VERSION 5.7 ;
  NOWIREEXTENSIONATPIN ON ;
  DIVIDERCHAR "/" ;
  BUSBITCHARS "[]" ;
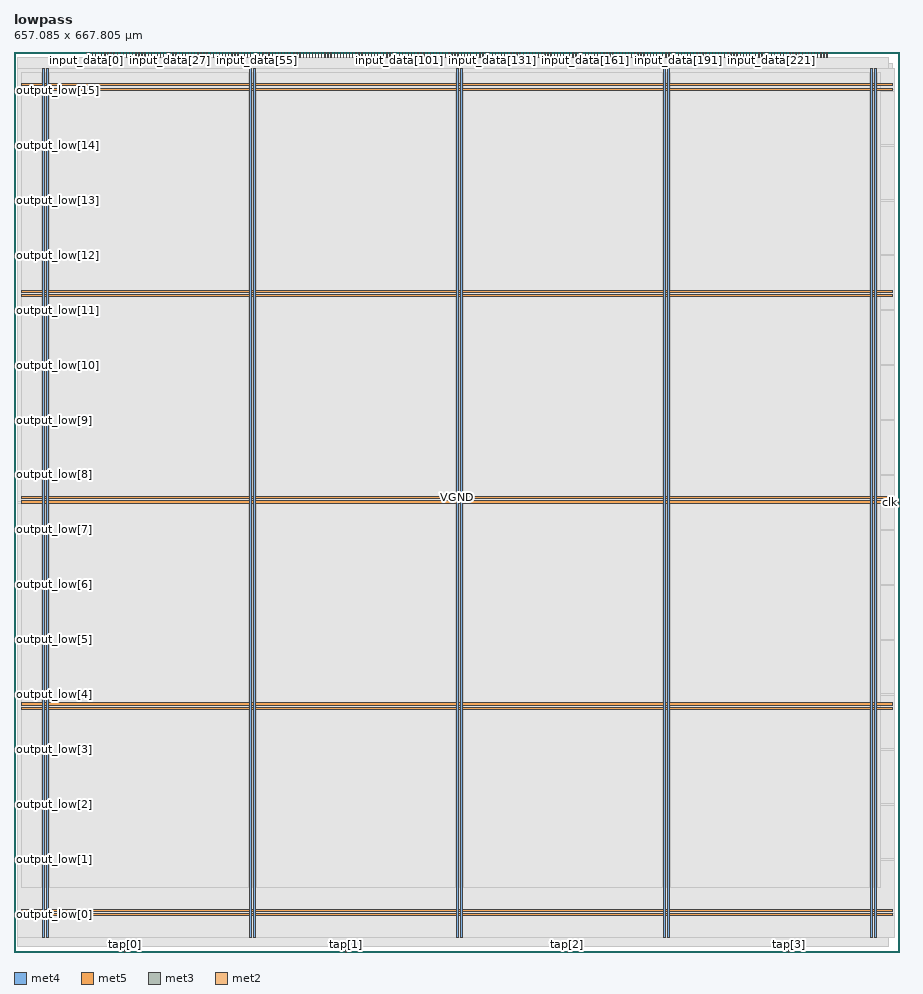
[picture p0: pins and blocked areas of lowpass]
MACRO lowpass
  CLASS BLOCK ;
  FOREIGN lowpass ;
  ORIGIN 0.000 0.000 ;
  SIZE 657.085 BY 667.805 ;
  PIN VGND
    DIRECTION INOUT ;
    USE GROUND ;
    PORT
      LAYER met4 ;
        RECT 24.340 10.640 25.940 655.760 ;
    END
    PORT
      LAYER met4 ;
        RECT 177.940 10.640 179.540 655.760 ;
    END
    PORT
      LAYER met4 ;
        RECT 331.540 10.640 333.140 655.760 ;
    END
    PORT
      LAYER met4 ;
        RECT 485.140 10.640 486.740 655.760 ;
    END
    PORT
      LAYER met4 ;
        RECT 638.740 10.640 640.340 655.760 ;
    END
    PORT
      LAYER met5 ;
        RECT 5.280 30.030 651.600 31.630 ;
    END
    PORT
      LAYER met5 ;
        RECT 5.280 183.210 651.600 184.810 ;
    END
    PORT
      LAYER met5 ;
        RECT 5.280 336.390 651.600 337.990 ;
    END
    PORT
      LAYER met5 ;
        RECT 5.280 489.570 651.600 491.170 ;
    END
    PORT
      LAYER met5 ;
        RECT 5.280 642.750 651.600 644.350 ;
    END
  END VGND
  PIN VPWR
    DIRECTION INOUT ;
    USE POWER ;
    PORT
      LAYER met4 ;
        RECT 21.040 10.640 22.640 655.760 ;
    END
    PORT
      LAYER met4 ;
        RECT 174.640 10.640 176.240 655.760 ;
    END
    PORT
      LAYER met4 ;
        RECT 328.240 10.640 329.840 655.760 ;
    END
    PORT
      LAYER met4 ;
        RECT 481.840 10.640 483.440 655.760 ;
    END
    PORT
      LAYER met4 ;
        RECT 635.440 10.640 637.040 655.760 ;
    END
    PORT
      LAYER met5 ;
        RECT 5.280 26.730 651.600 28.330 ;
    END
    PORT
      LAYER met5 ;
        RECT 5.280 179.910 651.600 181.510 ;
    END
    PORT
      LAYER met5 ;
        RECT 5.280 333.090 651.600 334.690 ;
    END
    PORT
      LAYER met5 ;
        RECT 5.280 486.270 651.600 487.870 ;
    END
    PORT
      LAYER met5 ;
        RECT 5.280 639.450 651.600 641.050 ;
    END
  END VPWR
  PIN clk
    DIRECTION INPUT ;
    USE SIGNAL ;
    ANTENNAGATEAREA 0.852000 ;
    ANTENNADIFFAREA 0.434700 ;
    PORT
      LAYER met3 ;
        RECT 653.085 333.240 657.085 333.840 ;
    END
  END clk
  PIN input_data[0]
    DIRECTION INPUT ;
    USE SIGNAL ;
    ANTENNAGATEAREA 0.213000 ;
    PORT
      LAYER met2 ;
        RECT 53.450 663.805 53.730 667.805 ;
    END
  END input_data[0]
  PIN input_data[100]
    DIRECTION INPUT ;
    USE SIGNAL ;
    ANTENNAGATEAREA 0.213000 ;
    PORT
      LAYER met2 ;
        RECT 283.450 663.805 283.730 667.805 ;
    END
  END input_data[100]
  PIN input_data[101]
    DIRECTION INPUT ;
    USE SIGNAL ;
    ANTENNAGATEAREA 0.213000 ;
    PORT
      LAYER met2 ;
        RECT 285.750 663.805 286.030 667.805 ;
    END
  END input_data[101]
  PIN input_data[102]
    DIRECTION INPUT ;
    USE SIGNAL ;
    ANTENNAGATEAREA 0.213000 ;
    PORT
      LAYER met2 ;
        RECT 288.050 663.805 288.330 667.805 ;
    END
  END input_data[102]
  PIN input_data[103]
    DIRECTION INPUT ;
    USE SIGNAL ;
    ANTENNAGATEAREA 0.213000 ;
    PORT
      LAYER met2 ;
        RECT 290.350 663.805 290.630 667.805 ;
    END
  END input_data[103]
  PIN input_data[104]
    DIRECTION INPUT ;
    USE SIGNAL ;
    ANTENNAGATEAREA 0.213000 ;
    PORT
      LAYER met2 ;
        RECT 292.650 663.805 292.930 667.805 ;
    END
  END input_data[104]
  PIN input_data[105]
    DIRECTION INPUT ;
    USE SIGNAL ;
    ANTENNAGATEAREA 0.213000 ;
    PORT
      LAYER met2 ;
        RECT 294.950 663.805 295.230 667.805 ;
    END
  END input_data[105]
  PIN input_data[106]
    DIRECTION INPUT ;
    USE SIGNAL ;
    ANTENNAGATEAREA 0.247500 ;
    PORT
      LAYER met2 ;
        RECT 297.250 663.805 297.530 667.805 ;
    END
  END input_data[106]
  PIN input_data[107]
    DIRECTION INPUT ;
    USE SIGNAL ;
    ANTENNAGATEAREA 0.247500 ;
    PORT
      LAYER met2 ;
        RECT 299.550 663.805 299.830 667.805 ;
    END
  END input_data[107]
  PIN input_data[108]
    DIRECTION INPUT ;
    USE SIGNAL ;
    ANTENNAGATEAREA 0.196500 ;
    PORT
      LAYER met2 ;
        RECT 301.850 663.805 302.130 667.805 ;
    END
  END input_data[108]
  PIN input_data[109]
    DIRECTION INPUT ;
    USE SIGNAL ;
    ANTENNAGATEAREA 0.247500 ;
    PORT
      LAYER met2 ;
        RECT 304.150 663.805 304.430 667.805 ;
    END
  END input_data[109]
  PIN input_data[10]
    DIRECTION INPUT ;
    USE SIGNAL ;
    ANTENNAGATEAREA 0.196500 ;
    PORT
      LAYER met2 ;
        RECT 76.450 663.805 76.730 667.805 ;
    END
  END input_data[10]
  PIN input_data[110]
    DIRECTION INPUT ;
    USE SIGNAL ;
    ANTENNAGATEAREA 0.247500 ;
    PORT
      LAYER met2 ;
        RECT 306.450 663.805 306.730 667.805 ;
    END
  END input_data[110]
  PIN input_data[111]
    DIRECTION INPUT ;
    USE SIGNAL ;
    ANTENNAGATEAREA 0.196500 ;
    PORT
      LAYER met2 ;
        RECT 308.750 663.805 309.030 667.805 ;
    END
  END input_data[111]
  PIN input_data[112]
    DIRECTION INPUT ;
    USE SIGNAL ;
    ANTENNAGATEAREA 0.213000 ;
    PORT
      LAYER met2 ;
        RECT 311.050 663.805 311.330 667.805 ;
    END
  END input_data[112]
  PIN input_data[113]
    DIRECTION INPUT ;
    USE SIGNAL ;
    ANTENNAGATEAREA 0.426000 ;
    PORT
      LAYER met2 ;
        RECT 313.350 663.805 313.630 667.805 ;
    END
  END input_data[113]
  PIN input_data[114]
    DIRECTION INPUT ;
    USE SIGNAL ;
    ANTENNAGATEAREA 0.196500 ;
    PORT
      LAYER met2 ;
        RECT 315.650 663.805 315.930 667.805 ;
    END
  END input_data[114]
  PIN input_data[115]
    DIRECTION INPUT ;
    USE SIGNAL ;
    ANTENNAGATEAREA 0.196500 ;
    PORT
      LAYER met2 ;
        RECT 317.950 663.805 318.230 667.805 ;
    END
  END input_data[115]
  PIN input_data[116]
    DIRECTION INPUT ;
    USE SIGNAL ;
    ANTENNAGATEAREA 0.196500 ;
    PORT
      LAYER met2 ;
        RECT 320.250 663.805 320.530 667.805 ;
    END
  END input_data[116]
  PIN input_data[117]
    DIRECTION INPUT ;
    USE SIGNAL ;
    ANTENNAGATEAREA 0.196500 ;
    PORT
      LAYER met2 ;
        RECT 322.550 663.805 322.830 667.805 ;
    END
  END input_data[117]
  PIN input_data[118]
    DIRECTION INPUT ;
    USE SIGNAL ;
    ANTENNAGATEAREA 0.196500 ;
    PORT
      LAYER met2 ;
        RECT 324.850 663.805 325.130 667.805 ;
    END
  END input_data[118]
  PIN input_data[119]
    DIRECTION INPUT ;
    USE SIGNAL ;
    ANTENNAGATEAREA 0.196500 ;
    PORT
      LAYER met2 ;
        RECT 327.150 663.805 327.430 667.805 ;
    END
  END input_data[119]
  PIN input_data[11]
    DIRECTION INPUT ;
    USE SIGNAL ;
    ANTENNAGATEAREA 0.196500 ;
    PORT
      LAYER met2 ;
        RECT 78.750 663.805 79.030 667.805 ;
    END
  END input_data[11]
  PIN input_data[120]
    DIRECTION INPUT ;
    USE SIGNAL ;
    ANTENNAGATEAREA 0.196500 ;
    PORT
      LAYER met2 ;
        RECT 329.450 663.805 329.730 667.805 ;
    END
  END input_data[120]
  PIN input_data[121]
    DIRECTION INPUT ;
    USE SIGNAL ;
    ANTENNAGATEAREA 0.159000 ;
    PORT
      LAYER met2 ;
        RECT 331.750 663.805 332.030 667.805 ;
    END
  END input_data[121]
  PIN input_data[122]
    DIRECTION INPUT ;
    USE SIGNAL ;
    ANTENNAGATEAREA 0.196500 ;
    PORT
      LAYER met2 ;
        RECT 334.050 663.805 334.330 667.805 ;
    END
  END input_data[122]
  PIN input_data[123]
    DIRECTION INPUT ;
    USE SIGNAL ;
    ANTENNAGATEAREA 0.196500 ;
    PORT
      LAYER met2 ;
        RECT 336.350 663.805 336.630 667.805 ;
    END
  END input_data[123]
  PIN input_data[124]
    DIRECTION INPUT ;
    USE SIGNAL ;
    ANTENNAGATEAREA 0.196500 ;
    PORT
      LAYER met2 ;
        RECT 338.650 663.805 338.930 667.805 ;
    END
  END input_data[124]
  PIN input_data[125]
    DIRECTION INPUT ;
    USE SIGNAL ;
    ANTENNAGATEAREA 0.126000 ;
    PORT
      LAYER met2 ;
        RECT 340.950 663.805 341.230 667.805 ;
    END
  END input_data[125]
  PIN input_data[126]
    DIRECTION INPUT ;
    USE SIGNAL ;
    ANTENNAGATEAREA 0.159000 ;
    PORT
      LAYER met2 ;
        RECT 343.250 663.805 343.530 667.805 ;
    END
  END input_data[126]
  PIN input_data[127]
    DIRECTION INPUT ;
    USE SIGNAL ;
    ANTENNAGATEAREA 0.196500 ;
    PORT
      LAYER met2 ;
        RECT 345.550 663.805 345.830 667.805 ;
    END
  END input_data[127]
  PIN input_data[128]
    DIRECTION INPUT ;
    USE SIGNAL ;
    ANTENNAGATEAREA 0.159000 ;
    PORT
      LAYER met2 ;
        RECT 347.850 663.805 348.130 667.805 ;
    END
  END input_data[128]
  PIN input_data[129]
    DIRECTION INPUT ;
    USE SIGNAL ;
    ANTENNAGATEAREA 0.159000 ;
    PORT
      LAYER met2 ;
        RECT 350.150 663.805 350.430 667.805 ;
    END
  END input_data[129]
  PIN input_data[12]
    DIRECTION INPUT ;
    USE SIGNAL ;
    ANTENNAGATEAREA 0.196500 ;
    PORT
      LAYER met2 ;
        RECT 81.050 663.805 81.330 667.805 ;
    END
  END input_data[12]
  PIN input_data[130]
    DIRECTION INPUT ;
    USE SIGNAL ;
    ANTENNAGATEAREA 0.159000 ;
    PORT
      LAYER met2 ;
        RECT 352.450 663.805 352.730 667.805 ;
    END
  END input_data[130]
  PIN input_data[131]
    DIRECTION INPUT ;
    USE SIGNAL ;
    ANTENNAGATEAREA 0.495000 ;
    PORT
      LAYER met2 ;
        RECT 354.750 663.805 355.030 667.805 ;
    END
  END input_data[131]
  PIN input_data[132]
    DIRECTION INPUT ;
    USE SIGNAL ;
    ANTENNAGATEAREA 0.247500 ;
    PORT
      LAYER met2 ;
        RECT 357.050 663.805 357.330 667.805 ;
    END
  END input_data[132]
  PIN input_data[133]
    DIRECTION INPUT ;
    USE SIGNAL ;
    ANTENNAGATEAREA 0.247500 ;
    PORT
      LAYER met2 ;
        RECT 359.350 663.805 359.630 667.805 ;
    END
  END input_data[133]
  PIN input_data[134]
    DIRECTION INPUT ;
    USE SIGNAL ;
    ANTENNAGATEAREA 0.159000 ;
    PORT
      LAYER met2 ;
        RECT 361.650 663.805 361.930 667.805 ;
    END
  END input_data[134]
  PIN input_data[135]
    DIRECTION INPUT ;
    USE SIGNAL ;
    ANTENNAGATEAREA 0.247500 ;
    PORT
      LAYER met2 ;
        RECT 363.950 663.805 364.230 667.805 ;
    END
  END input_data[135]
  PIN input_data[136]
    DIRECTION INPUT ;
    USE SIGNAL ;
    ANTENNAGATEAREA 0.159000 ;
    PORT
      LAYER met2 ;
        RECT 366.250 663.805 366.530 667.805 ;
    END
  END input_data[136]
  PIN input_data[137]
    DIRECTION INPUT ;
    USE SIGNAL ;
    ANTENNAGATEAREA 0.213000 ;
    PORT
      LAYER met2 ;
        RECT 368.550 663.805 368.830 667.805 ;
    END
  END input_data[137]
  PIN input_data[138]
    DIRECTION INPUT ;
    USE SIGNAL ;
    ANTENNAGATEAREA 0.159000 ;
    PORT
      LAYER met2 ;
        RECT 370.850 663.805 371.130 667.805 ;
    END
  END input_data[138]
  PIN input_data[139]
    DIRECTION INPUT ;
    USE SIGNAL ;
    ANTENNAGATEAREA 0.213000 ;
    PORT
      LAYER met2 ;
        RECT 373.150 663.805 373.430 667.805 ;
    END
  END input_data[139]
  PIN input_data[13]
    DIRECTION INPUT ;
    USE SIGNAL ;
    ANTENNAGATEAREA 0.742500 ;
    PORT
      LAYER met2 ;
        RECT 83.350 663.805 83.630 667.805 ;
    END
  END input_data[13]
  PIN input_data[140]
    DIRECTION INPUT ;
    USE SIGNAL ;
    ANTENNAGATEAREA 0.159000 ;
    PORT
      LAYER met2 ;
        RECT 375.450 663.805 375.730 667.805 ;
    END
  END input_data[140]
  PIN input_data[141]
    DIRECTION INPUT ;
    USE SIGNAL ;
    ANTENNAGATEAREA 0.159000 ;
    PORT
      LAYER met2 ;
        RECT 377.750 663.805 378.030 667.805 ;
    END
  END input_data[141]
  PIN input_data[142]
    DIRECTION INPUT ;
    USE SIGNAL ;
    ANTENNAGATEAREA 0.426000 ;
    PORT
      LAYER met2 ;
        RECT 380.050 663.805 380.330 667.805 ;
    END
  END input_data[142]
  PIN input_data[143]
    DIRECTION INPUT ;
    USE SIGNAL ;
    ANTENNAGATEAREA 0.213000 ;
    PORT
      LAYER met2 ;
        RECT 382.350 663.805 382.630 667.805 ;
    END
  END input_data[143]
  PIN input_data[144]
    DIRECTION INPUT ;
    USE SIGNAL ;
    ANTENNAGATEAREA 0.247500 ;
    PORT
      LAYER met2 ;
        RECT 384.650 663.805 384.930 667.805 ;
    END
  END input_data[144]
  PIN input_data[145]
    DIRECTION INPUT ;
    USE SIGNAL ;
    ANTENNAGATEAREA 0.426000 ;
    PORT
      LAYER met2 ;
        RECT 386.950 663.805 387.230 667.805 ;
    END
  END input_data[145]
  PIN input_data[146]
    DIRECTION INPUT ;
    USE SIGNAL ;
    ANTENNAGATEAREA 0.247500 ;
    PORT
      LAYER met2 ;
        RECT 389.250 663.805 389.530 667.805 ;
    END
  END input_data[146]
  PIN input_data[147]
    DIRECTION INPUT ;
    USE SIGNAL ;
    ANTENNAGATEAREA 0.126000 ;
    PORT
      LAYER met2 ;
        RECT 391.550 663.805 391.830 667.805 ;
    END
  END input_data[147]
  PIN input_data[148]
    DIRECTION INPUT ;
    USE SIGNAL ;
    ANTENNAGATEAREA 0.196500 ;
    PORT
      LAYER met2 ;
        RECT 393.850 663.805 394.130 667.805 ;
    END
  END input_data[148]
  PIN input_data[149]
    DIRECTION INPUT ;
    USE SIGNAL ;
    ANTENNAGATEAREA 0.196500 ;
    PORT
      LAYER met2 ;
        RECT 396.150 663.805 396.430 667.805 ;
    END
  END input_data[149]
  PIN input_data[14]
    DIRECTION INPUT ;
    USE SIGNAL ;
    ANTENNAGATEAREA 0.247500 ;
    PORT
      LAYER met2 ;
        RECT 85.650 663.805 85.930 667.805 ;
    END
  END input_data[14]
  PIN input_data[150]
    DIRECTION INPUT ;
    USE SIGNAL ;
    ANTENNAGATEAREA 0.213000 ;
    PORT
      LAYER met2 ;
        RECT 398.450 663.805 398.730 667.805 ;
    END
  END input_data[150]
  PIN input_data[151]
    DIRECTION INPUT ;
    USE SIGNAL ;
    ANTENNAGATEAREA 0.247500 ;
    PORT
      LAYER met2 ;
        RECT 400.750 663.805 401.030 667.805 ;
    END
  END input_data[151]
  PIN input_data[152]
    DIRECTION INPUT ;
    USE SIGNAL ;
    ANTENNAGATEAREA 0.247500 ;
    PORT
      LAYER met2 ;
        RECT 403.050 663.805 403.330 667.805 ;
    END
  END input_data[152]
  PIN input_data[153]
    DIRECTION INPUT ;
    USE SIGNAL ;
    ANTENNAGATEAREA 0.196500 ;
    PORT
      LAYER met2 ;
        RECT 405.350 663.805 405.630 667.805 ;
    END
  END input_data[153]
  PIN input_data[154]
    DIRECTION INPUT ;
    USE SIGNAL ;
    ANTENNAGATEAREA 0.159000 ;
    PORT
      LAYER met2 ;
        RECT 407.650 663.805 407.930 667.805 ;
    END
  END input_data[154]
  PIN input_data[155]
    DIRECTION INPUT ;
    USE SIGNAL ;
    ANTENNAGATEAREA 0.196500 ;
    PORT
      LAYER met2 ;
        RECT 409.950 663.805 410.230 667.805 ;
    END
  END input_data[155]
  PIN input_data[156]
    DIRECTION INPUT ;
    USE SIGNAL ;
    ANTENNAGATEAREA 0.213000 ;
    PORT
      LAYER met2 ;
        RECT 412.250 663.805 412.530 667.805 ;
    END
  END input_data[156]
  PIN input_data[157]
    DIRECTION INPUT ;
    USE SIGNAL ;
    ANTENNAGATEAREA 0.213000 ;
    PORT
      LAYER met2 ;
        RECT 414.550 663.805 414.830 667.805 ;
    END
  END input_data[157]
  PIN input_data[158]
    DIRECTION INPUT ;
    USE SIGNAL ;
    ANTENNAGATEAREA 0.247500 ;
    PORT
      LAYER met2 ;
        RECT 416.850 663.805 417.130 667.805 ;
    END
  END input_data[158]
  PIN input_data[159]
    DIRECTION INPUT ;
    USE SIGNAL ;
    ANTENNAGATEAREA 0.196500 ;
    PORT
      LAYER met2 ;
        RECT 419.150 663.805 419.430 667.805 ;
    END
  END input_data[159]
  PIN input_data[15]
    DIRECTION INPUT ;
    USE SIGNAL ;
    PORT
      LAYER met2 ;
        RECT 87.950 663.805 88.230 667.805 ;
    END
  END input_data[15]
  PIN input_data[160]
    DIRECTION INPUT ;
    USE SIGNAL ;
    ANTENNAGATEAREA 0.213000 ;
    PORT
      LAYER met2 ;
        RECT 421.450 663.805 421.730 667.805 ;
    END
  END input_data[160]
  PIN input_data[161]
    DIRECTION INPUT ;
    USE SIGNAL ;
    ANTENNAGATEAREA 0.213000 ;
    PORT
      LAYER met2 ;
        RECT 423.750 663.805 424.030 667.805 ;
    END
  END input_data[161]
  PIN input_data[162]
    DIRECTION INPUT ;
    USE SIGNAL ;
    ANTENNAGATEAREA 0.196500 ;
    PORT
      LAYER met2 ;
        RECT 426.050 663.805 426.330 667.805 ;
    END
  END input_data[162]
  PIN input_data[163]
    DIRECTION INPUT ;
    USE SIGNAL ;
    ANTENNAGATEAREA 0.196500 ;
    PORT
      LAYER met2 ;
        RECT 428.350 663.805 428.630 667.805 ;
    END
  END input_data[163]
  PIN input_data[164]
    DIRECTION INPUT ;
    USE SIGNAL ;
    ANTENNAGATEAREA 0.196500 ;
    PORT
      LAYER met2 ;
        RECT 430.650 663.805 430.930 667.805 ;
    END
  END input_data[164]
  PIN input_data[165]
    DIRECTION INPUT ;
    USE SIGNAL ;
    ANTENNAGATEAREA 0.196500 ;
    PORT
      LAYER met2 ;
        RECT 432.950 663.805 433.230 667.805 ;
    END
  END input_data[165]
  PIN input_data[166]
    DIRECTION INPUT ;
    USE SIGNAL ;
    ANTENNAGATEAREA 0.213000 ;
    PORT
      LAYER met2 ;
        RECT 435.250 663.805 435.530 667.805 ;
    END
  END input_data[166]
  PIN input_data[167]
    DIRECTION INPUT ;
    USE SIGNAL ;
    ANTENNAGATEAREA 0.213000 ;
    PORT
      LAYER met2 ;
        RECT 437.550 663.805 437.830 667.805 ;
    END
  END input_data[167]
  PIN input_data[168]
    DIRECTION INPUT ;
    USE SIGNAL ;
    ANTENNAGATEAREA 0.196500 ;
    PORT
      LAYER met2 ;
        RECT 439.850 663.805 440.130 667.805 ;
    END
  END input_data[168]
  PIN input_data[169]
    DIRECTION INPUT ;
    USE SIGNAL ;
    ANTENNAGATEAREA 0.196500 ;
    PORT
      LAYER met2 ;
        RECT 442.150 663.805 442.430 667.805 ;
    END
  END input_data[169]
  PIN input_data[16]
    DIRECTION INPUT ;
    USE SIGNAL ;
    ANTENNAGATEAREA 0.247500 ;
    PORT
      LAYER met2 ;
        RECT 90.250 663.805 90.530 667.805 ;
    END
  END input_data[16]
  PIN input_data[170]
    DIRECTION INPUT ;
    USE SIGNAL ;
    ANTENNAGATEAREA 0.196500 ;
    PORT
      LAYER met2 ;
        RECT 444.450 663.805 444.730 667.805 ;
    END
  END input_data[170]
  PIN input_data[171]
    DIRECTION INPUT ;
    USE SIGNAL ;
    ANTENNAGATEAREA 0.213000 ;
    PORT
      LAYER met2 ;
        RECT 446.750 663.805 447.030 667.805 ;
    END
  END input_data[171]
  PIN input_data[172]
    DIRECTION INPUT ;
    USE SIGNAL ;
    ANTENNAGATEAREA 0.196500 ;
    PORT
      LAYER met2 ;
        RECT 449.050 663.805 449.330 667.805 ;
    END
  END input_data[172]
  PIN input_data[173]
    DIRECTION INPUT ;
    USE SIGNAL ;
    ANTENNAGATEAREA 0.213000 ;
    PORT
      LAYER met2 ;
        RECT 451.350 663.805 451.630 667.805 ;
    END
  END input_data[173]
  PIN input_data[174]
    DIRECTION INPUT ;
    USE SIGNAL ;
    ANTENNAGATEAREA 0.159000 ;
    PORT
      LAYER met2 ;
        RECT 453.650 663.805 453.930 667.805 ;
    END
  END input_data[174]
  PIN input_data[175]
    DIRECTION INPUT ;
    USE SIGNAL ;
    PORT
      LAYER met2 ;
        RECT 455.950 663.805 456.230 667.805 ;
    END
  END input_data[175]
  PIN input_data[176]
    DIRECTION INPUT ;
    USE SIGNAL ;
    ANTENNAGATEAREA 0.213000 ;
    PORT
      LAYER met2 ;
        RECT 458.250 663.805 458.530 667.805 ;
    END
  END input_data[176]
  PIN input_data[177]
    DIRECTION INPUT ;
    USE SIGNAL ;
    ANTENNAGATEAREA 0.213000 ;
    PORT
      LAYER met2 ;
        RECT 460.550 663.805 460.830 667.805 ;
    END
  END input_data[177]
  PIN input_data[178]
    DIRECTION INPUT ;
    USE SIGNAL ;
    ANTENNAGATEAREA 0.213000 ;
    PORT
      LAYER met2 ;
        RECT 462.850 663.805 463.130 667.805 ;
    END
  END input_data[178]
  PIN input_data[179]
    DIRECTION INPUT ;
    USE SIGNAL ;
    ANTENNAGATEAREA 0.213000 ;
    PORT
      LAYER met2 ;
        RECT 465.150 663.805 465.430 667.805 ;
    END
  END input_data[179]
  PIN input_data[17]
    DIRECTION INPUT ;
    USE SIGNAL ;
    ANTENNAGATEAREA 0.426000 ;
    PORT
      LAYER met2 ;
        RECT 92.550 663.805 92.830 667.805 ;
    END
  END input_data[17]
  PIN input_data[180]
    DIRECTION INPUT ;
    USE SIGNAL ;
    ANTENNAGATEAREA 0.213000 ;
    PORT
      LAYER met2 ;
        RECT 467.450 663.805 467.730 667.805 ;
    END
  END input_data[180]
  PIN input_data[181]
    DIRECTION INPUT ;
    USE SIGNAL ;
    ANTENNAGATEAREA 0.213000 ;
    PORT
      LAYER met2 ;
        RECT 469.750 663.805 470.030 667.805 ;
    END
  END input_data[181]
  PIN input_data[182]
    DIRECTION INPUT ;
    USE SIGNAL ;
    ANTENNAGATEAREA 0.126000 ;
    PORT
      LAYER met2 ;
        RECT 472.050 663.805 472.330 667.805 ;
    END
  END input_data[182]
  PIN input_data[183]
    DIRECTION INPUT ;
    USE SIGNAL ;
    ANTENNAGATEAREA 0.213000 ;
    PORT
      LAYER met2 ;
        RECT 474.350 663.805 474.630 667.805 ;
    END
  END input_data[183]
  PIN input_data[184]
    DIRECTION INPUT ;
    USE SIGNAL ;
    ANTENNAGATEAREA 0.159000 ;
    PORT
      LAYER met2 ;
        RECT 476.650 663.805 476.930 667.805 ;
    END
  END input_data[184]
  PIN input_data[185]
    DIRECTION INPUT ;
    USE SIGNAL ;
    ANTENNAGATEAREA 0.213000 ;
    PORT
      LAYER met2 ;
        RECT 478.950 663.805 479.230 667.805 ;
    END
  END input_data[185]
  PIN input_data[186]
    DIRECTION INPUT ;
    USE SIGNAL ;
    ANTENNAGATEAREA 0.159000 ;
    PORT
      LAYER met2 ;
        RECT 481.250 663.805 481.530 667.805 ;
    END
  END input_data[186]
  PIN input_data[187]
    DIRECTION INPUT ;
    USE SIGNAL ;
    ANTENNAGATEAREA 0.247500 ;
    PORT
      LAYER met2 ;
        RECT 483.550 663.805 483.830 667.805 ;
    END
  END input_data[187]
  PIN input_data[188]
    DIRECTION INPUT ;
    USE SIGNAL ;
    ANTENNAGATEAREA 0.247500 ;
    PORT
      LAYER met2 ;
        RECT 485.850 663.805 486.130 667.805 ;
    END
  END input_data[188]
  PIN input_data[189]
    DIRECTION INPUT ;
    USE SIGNAL ;
    ANTENNAGATEAREA 0.159000 ;
    PORT
      LAYER met2 ;
        RECT 488.150 663.805 488.430 667.805 ;
    END
  END input_data[189]
  PIN input_data[18]
    DIRECTION INPUT ;
    USE SIGNAL ;
    ANTENNAGATEAREA 0.213000 ;
    PORT
      LAYER met2 ;
        RECT 94.850 663.805 95.130 667.805 ;
    END
  END input_data[18]
  PIN input_data[190]
    DIRECTION INPUT ;
    USE SIGNAL ;
    ANTENNAGATEAREA 0.196500 ;
    PORT
      LAYER met2 ;
        RECT 490.450 663.805 490.730 667.805 ;
    END
  END input_data[190]
  PIN input_data[191]
    DIRECTION INPUT ;
    USE SIGNAL ;
    PORT
      LAYER met2 ;
        RECT 492.750 663.805 493.030 667.805 ;
    END
  END input_data[191]
  PIN input_data[192]
    DIRECTION INPUT ;
    USE SIGNAL ;
    ANTENNAGATEAREA 0.426000 ;
    PORT
      LAYER met2 ;
        RECT 495.050 663.805 495.330 667.805 ;
    END
  END input_data[192]
  PIN input_data[193]
    DIRECTION INPUT ;
    USE SIGNAL ;
    ANTENNAGATEAREA 0.495000 ;
    PORT
      LAYER met2 ;
        RECT 497.350 663.805 497.630 667.805 ;
    END
  END input_data[193]
  PIN input_data[194]
    DIRECTION INPUT ;
    USE SIGNAL ;
    ANTENNAGATEAREA 0.495000 ;
    PORT
      LAYER met2 ;
        RECT 499.650 663.805 499.930 667.805 ;
    END
  END input_data[194]
  PIN input_data[195]
    DIRECTION INPUT ;
    USE SIGNAL ;
    ANTENNAGATEAREA 0.426000 ;
    PORT
      LAYER met2 ;
        RECT 501.950 663.805 502.230 667.805 ;
    END
  END input_data[195]
  PIN input_data[196]
    DIRECTION INPUT ;
    USE SIGNAL ;
    ANTENNAGATEAREA 0.426000 ;
    PORT
      LAYER met2 ;
        RECT 504.250 663.805 504.530 667.805 ;
    END
  END input_data[196]
  PIN input_data[197]
    DIRECTION INPUT ;
    USE SIGNAL ;
    ANTENNAGATEAREA 0.426000 ;
    PORT
      LAYER met2 ;
        RECT 506.550 663.805 506.830 667.805 ;
    END
  END input_data[197]
  PIN input_data[198]
    DIRECTION INPUT ;
    USE SIGNAL ;
    ANTENNAGATEAREA 0.426000 ;
    PORT
      LAYER met2 ;
        RECT 508.850 663.805 509.130 667.805 ;
    END
  END input_data[198]
  PIN input_data[199]
    DIRECTION INPUT ;
    USE SIGNAL ;
    ANTENNAGATEAREA 0.247500 ;
    PORT
      LAYER met2 ;
        RECT 511.150 663.805 511.430 667.805 ;
    END
  END input_data[199]
  PIN input_data[19]
    DIRECTION INPUT ;
    USE SIGNAL ;
    ANTENNAGATEAREA 0.213000 ;
    PORT
      LAYER met2 ;
        RECT 97.150 663.805 97.430 667.805 ;
    END
  END input_data[19]
  PIN input_data[1]
    DIRECTION INPUT ;
    USE SIGNAL ;
    ANTENNAGATEAREA 0.196500 ;
    PORT
      LAYER met2 ;
        RECT 55.750 663.805 56.030 667.805 ;
    END
  END input_data[1]
  PIN input_data[200]
    DIRECTION INPUT ;
    USE SIGNAL ;
    ANTENNAGATEAREA 0.247500 ;
    PORT
      LAYER met2 ;
        RECT 513.450 663.805 513.730 667.805 ;
    END
  END input_data[200]
  PIN input_data[201]
    DIRECTION INPUT ;
    USE SIGNAL ;
    ANTENNAGATEAREA 0.247500 ;
    PORT
      LAYER met2 ;
        RECT 515.750 663.805 516.030 667.805 ;
    END
  END input_data[201]
  PIN input_data[202]
    DIRECTION INPUT ;
    USE SIGNAL ;
    ANTENNAGATEAREA 0.247500 ;
    PORT
      LAYER met2 ;
        RECT 518.050 663.805 518.330 667.805 ;
    END
  END input_data[202]
  PIN input_data[203]
    DIRECTION INPUT ;
    USE SIGNAL ;
    ANTENNAGATEAREA 0.247500 ;
    PORT
      LAYER met2 ;
        RECT 520.350 663.805 520.630 667.805 ;
    END
  END input_data[203]
  PIN input_data[204]
    DIRECTION INPUT ;
    USE SIGNAL ;
    ANTENNAGATEAREA 0.426000 ;
    PORT
      LAYER met2 ;
        RECT 522.650 663.805 522.930 667.805 ;
    END
  END input_data[204]
  PIN input_data[205]
    DIRECTION INPUT ;
    USE SIGNAL ;
    ANTENNAGATEAREA 0.247500 ;
    PORT
      LAYER met2 ;
        RECT 524.950 663.805 525.230 667.805 ;
    END
  END input_data[205]
  PIN input_data[206]
    DIRECTION INPUT ;
    USE SIGNAL ;
    ANTENNAGATEAREA 0.213000 ;
    PORT
      LAYER met2 ;
        RECT 527.250 663.805 527.530 667.805 ;
    END
  END input_data[206]
  PIN input_data[207]
    DIRECTION INPUT ;
    USE SIGNAL ;
    ANTENNAGATEAREA 0.213000 ;
    PORT
      LAYER met2 ;
        RECT 529.550 663.805 529.830 667.805 ;
    END
  END input_data[207]
  PIN input_data[208]
    DIRECTION INPUT ;
    USE SIGNAL ;
    ANTENNAGATEAREA 0.159000 ;
    PORT
      LAYER met2 ;
        RECT 531.850 663.805 532.130 667.805 ;
    END
  END input_data[208]
  PIN input_data[209]
    DIRECTION INPUT ;
    USE SIGNAL ;
    ANTENNAGATEAREA 0.742500 ;
    PORT
      LAYER met2 ;
        RECT 534.150 663.805 534.430 667.805 ;
    END
  END input_data[209]
  PIN input_data[20]
    DIRECTION INPUT ;
    USE SIGNAL ;
    ANTENNAGATEAREA 0.426000 ;
    PORT
      LAYER met2 ;
        RECT 99.450 663.805 99.730 667.805 ;
    END
  END input_data[20]
  PIN input_data[210]
    DIRECTION INPUT ;
    USE SIGNAL ;
    ANTENNAGATEAREA 0.495000 ;
    PORT
      LAYER met2 ;
        RECT 536.450 663.805 536.730 667.805 ;
    END
  END input_data[210]
  PIN input_data[211]
    DIRECTION INPUT ;
    USE SIGNAL ;
    ANTENNAGATEAREA 0.742500 ;
    PORT
      LAYER met2 ;
        RECT 538.750 663.805 539.030 667.805 ;
    END
  END input_data[211]
  PIN input_data[212]
    DIRECTION INPUT ;
    USE SIGNAL ;
    ANTENNAGATEAREA 0.742500 ;
    PORT
      LAYER met2 ;
        RECT 541.050 663.805 541.330 667.805 ;
    END
  END input_data[212]
  PIN input_data[213]
    DIRECTION INPUT ;
    USE SIGNAL ;
    ANTENNAGATEAREA 0.495000 ;
    PORT
      LAYER met2 ;
        RECT 543.350 663.805 543.630 667.805 ;
    END
  END input_data[213]
  PIN input_data[214]
    DIRECTION INPUT ;
    USE SIGNAL ;
    ANTENNAGATEAREA 0.495000 ;
    PORT
      LAYER met2 ;
        RECT 545.650 663.805 545.930 667.805 ;
    END
  END input_data[214]
  PIN input_data[215]
    DIRECTION INPUT ;
    USE SIGNAL ;
    ANTENNAGATEAREA 0.495000 ;
    PORT
      LAYER met2 ;
        RECT 547.950 663.805 548.230 667.805 ;
    END
  END input_data[215]
  PIN input_data[216]
    DIRECTION INPUT ;
    USE SIGNAL ;
    ANTENNAGATEAREA 0.426000 ;
    PORT
      LAYER met2 ;
        RECT 550.250 663.805 550.530 667.805 ;
    END
  END input_data[216]
  PIN input_data[217]
    DIRECTION INPUT ;
    USE SIGNAL ;
    ANTENNAGATEAREA 0.247500 ;
    PORT
      LAYER met2 ;
        RECT 552.550 663.805 552.830 667.805 ;
    END
  END input_data[217]
  PIN input_data[218]
    DIRECTION INPUT ;
    USE SIGNAL ;
    ANTENNAGATEAREA 0.213000 ;
    PORT
      LAYER met2 ;
        RECT 554.850 663.805 555.130 667.805 ;
    END
  END input_data[218]
  PIN input_data[219]
    DIRECTION INPUT ;
    USE SIGNAL ;
    ANTENNAGATEAREA 0.213000 ;
    PORT
      LAYER met2 ;
        RECT 557.150 663.805 557.430 667.805 ;
    END
  END input_data[219]
  PIN input_data[21]
    DIRECTION INPUT ;
    USE SIGNAL ;
    ANTENNAGATEAREA 0.213000 ;
    PORT
      LAYER met2 ;
        RECT 101.750 663.805 102.030 667.805 ;
    END
  END input_data[21]
  PIN input_data[220]
    DIRECTION INPUT ;
    USE SIGNAL ;
    ANTENNAGATEAREA 0.213000 ;
    PORT
      LAYER met2 ;
        RECT 559.450 663.805 559.730 667.805 ;
    END
  END input_data[220]
  PIN input_data[221]
    DIRECTION INPUT ;
    USE SIGNAL ;
    ANTENNAGATEAREA 0.213000 ;
    PORT
      LAYER met2 ;
        RECT 561.750 663.805 562.030 667.805 ;
    END
  END input_data[221]
  PIN input_data[222]
    DIRECTION INPUT ;
    USE SIGNAL ;
    ANTENNAGATEAREA 0.213000 ;
    PORT
      LAYER met2 ;
        RECT 564.050 663.805 564.330 667.805 ;
    END
  END input_data[222]
  PIN input_data[223]
    DIRECTION INPUT ;
    USE SIGNAL ;
    PORT
      LAYER met2 ;
        RECT 566.350 663.805 566.630 667.805 ;
    END
  END input_data[223]
  PIN input_data[224]
    DIRECTION INPUT ;
    USE SIGNAL ;
    ANTENNAGATEAREA 0.196500 ;
    PORT
      LAYER met2 ;
        RECT 568.650 663.805 568.930 667.805 ;
    END
  END input_data[224]
  PIN input_data[225]
    DIRECTION INPUT ;
    USE SIGNAL ;
    ANTENNAGATEAREA 0.196500 ;
    PORT
      LAYER met2 ;
        RECT 570.950 663.805 571.230 667.805 ;
    END
  END input_data[225]
  PIN input_data[226]
    DIRECTION INPUT ;
    USE SIGNAL ;
    ANTENNAGATEAREA 0.426000 ;
    PORT
      LAYER met2 ;
        RECT 573.250 663.805 573.530 667.805 ;
    END
  END input_data[226]
  PIN input_data[227]
    DIRECTION INPUT ;
    USE SIGNAL ;
    ANTENNAGATEAREA 0.426000 ;
    PORT
      LAYER met2 ;
        RECT 575.550 663.805 575.830 667.805 ;
    END
  END input_data[227]
  PIN input_data[228]
    DIRECTION INPUT ;
    USE SIGNAL ;
    ANTENNAGATEAREA 0.247500 ;
    PORT
      LAYER met2 ;
        RECT 577.850 663.805 578.130 667.805 ;
    END
  END input_data[228]
  PIN input_data[229]
    DIRECTION INPUT ;
    USE SIGNAL ;
    ANTENNAGATEAREA 0.247500 ;
    PORT
      LAYER met2 ;
        RECT 580.150 663.805 580.430 667.805 ;
    END
  END input_data[229]
  PIN input_data[22]
    DIRECTION INPUT ;
    USE SIGNAL ;
    ANTENNAGATEAREA 0.213000 ;
    PORT
      LAYER met2 ;
        RECT 104.050 663.805 104.330 667.805 ;
    END
  END input_data[22]
  PIN input_data[230]
    DIRECTION INPUT ;
    USE SIGNAL ;
    ANTENNAGATEAREA 0.247500 ;
    PORT
      LAYER met2 ;
        RECT 582.450 663.805 582.730 667.805 ;
    END
  END input_data[230]
  PIN input_data[231]
    DIRECTION INPUT ;
    USE SIGNAL ;
    ANTENNAGATEAREA 0.247500 ;
    PORT
      LAYER met2 ;
        RECT 584.750 663.805 585.030 667.805 ;
    END
  END input_data[231]
  PIN input_data[232]
    DIRECTION INPUT ;
    USE SIGNAL ;
    ANTENNAGATEAREA 0.213000 ;
    PORT
      LAYER met2 ;
        RECT 587.050 663.805 587.330 667.805 ;
    END
  END input_data[232]
  PIN input_data[233]
    DIRECTION INPUT ;
    USE SIGNAL ;
    ANTENNAGATEAREA 0.159000 ;
    PORT
      LAYER met2 ;
        RECT 589.350 663.805 589.630 667.805 ;
    END
  END input_data[233]
  PIN input_data[234]
    DIRECTION INPUT ;
    USE SIGNAL ;
    ANTENNAGATEAREA 0.213000 ;
    PORT
      LAYER met2 ;
        RECT 591.650 663.805 591.930 667.805 ;
    END
  END input_data[234]
  PIN input_data[235]
    DIRECTION INPUT ;
    USE SIGNAL ;
    ANTENNAGATEAREA 0.196500 ;
    PORT
      LAYER met2 ;
        RECT 593.950 663.805 594.230 667.805 ;
    END
  END input_data[235]
  PIN input_data[236]
    DIRECTION INPUT ;
    USE SIGNAL ;
    ANTENNAGATEAREA 0.196500 ;
    PORT
      LAYER met2 ;
        RECT 596.250 663.805 596.530 667.805 ;
    END
  END input_data[236]
  PIN input_data[237]
    DIRECTION INPUT ;
    USE SIGNAL ;
    ANTENNAGATEAREA 0.196500 ;
    PORT
      LAYER met2 ;
        RECT 598.550 663.805 598.830 667.805 ;
    END
  END input_data[237]
  PIN input_data[238]
    DIRECTION INPUT ;
    USE SIGNAL ;
    PORT
      LAYER met2 ;
        RECT 600.850 663.805 601.130 667.805 ;
    END
  END input_data[238]
  PIN input_data[239]
    DIRECTION INPUT ;
    USE SIGNAL ;
    PORT
      LAYER met2 ;
        RECT 603.150 663.805 603.430 667.805 ;
    END
  END input_data[239]
  PIN input_data[23]
    DIRECTION INPUT ;
    USE SIGNAL ;
    ANTENNAGATEAREA 0.213000 ;
    PORT
      LAYER met2 ;
        RECT 106.350 663.805 106.630 667.805 ;
    END
  END input_data[23]
  PIN input_data[24]
    DIRECTION INPUT ;
    USE SIGNAL ;
    ANTENNAGATEAREA 0.159000 ;
    PORT
      LAYER met2 ;
        RECT 108.650 663.805 108.930 667.805 ;
    END
  END input_data[24]
  PIN input_data[25]
    DIRECTION INPUT ;
    USE SIGNAL ;
    ANTENNAGATEAREA 0.213000 ;
    PORT
      LAYER met2 ;
        RECT 110.950 663.805 111.230 667.805 ;
    END
  END input_data[25]
  PIN input_data[26]
    DIRECTION INPUT ;
    USE SIGNAL ;
    ANTENNAGATEAREA 0.159000 ;
    PORT
      LAYER met2 ;
        RECT 113.250 663.805 113.530 667.805 ;
    END
  END input_data[26]
  PIN input_data[27]
    DIRECTION INPUT ;
    USE SIGNAL ;
    ANTENNAGATEAREA 0.213000 ;
    PORT
      LAYER met2 ;
        RECT 115.550 663.805 115.830 667.805 ;
    END
  END input_data[27]
  PIN input_data[28]
    DIRECTION INPUT ;
    USE SIGNAL ;
    ANTENNAGATEAREA 0.213000 ;
    PORT
      LAYER met2 ;
        RECT 117.850 663.805 118.130 667.805 ;
    END
  END input_data[28]
  PIN input_data[29]
    DIRECTION INPUT ;
    USE SIGNAL ;
    ANTENNAGATEAREA 0.159000 ;
    PORT
      LAYER met2 ;
        RECT 120.150 663.805 120.430 667.805 ;
    END
  END input_data[29]
  PIN input_data[2]
    DIRECTION INPUT ;
    USE SIGNAL ;
    ANTENNAGATEAREA 0.196500 ;
    PORT
      LAYER met2 ;
        RECT 58.050 663.805 58.330 667.805 ;
    END
  END input_data[2]
  PIN input_data[30]
    DIRECTION INPUT ;
    USE SIGNAL ;
    ANTENNAGATEAREA 0.495000 ;
    PORT
      LAYER met2 ;
        RECT 122.450 663.805 122.730 667.805 ;
    END
  END input_data[30]
  PIN input_data[31]
    DIRECTION INPUT ;
    USE SIGNAL ;
    ANTENNAGATEAREA 0.247500 ;
    PORT
      LAYER met2 ;
        RECT 124.750 663.805 125.030 667.805 ;
    END
  END input_data[31]
  PIN input_data[32]
    DIRECTION INPUT ;
    USE SIGNAL ;
    ANTENNAGATEAREA 0.213000 ;
    PORT
      LAYER met2 ;
        RECT 127.050 663.805 127.330 667.805 ;
    END
  END input_data[32]
  PIN input_data[33]
    DIRECTION INPUT ;
    USE SIGNAL ;
    ANTENNAGATEAREA 0.247500 ;
    PORT
      LAYER met2 ;
        RECT 129.350 663.805 129.630 667.805 ;
    END
  END input_data[33]
  PIN input_data[34]
    DIRECTION INPUT ;
    USE SIGNAL ;
    ANTENNAGATEAREA 0.247500 ;
    PORT
      LAYER met2 ;
        RECT 131.650 663.805 131.930 667.805 ;
    END
  END input_data[34]
  PIN input_data[35]
    DIRECTION INPUT ;
    USE SIGNAL ;
    ANTENNAGATEAREA 0.159000 ;
    PORT
      LAYER met2 ;
        RECT 133.950 663.805 134.230 667.805 ;
    END
  END input_data[35]
  PIN input_data[36]
    DIRECTION INPUT ;
    USE SIGNAL ;
    ANTENNAGATEAREA 0.159000 ;
    PORT
      LAYER met2 ;
        RECT 136.250 663.805 136.530 667.805 ;
    END
  END input_data[36]
  PIN input_data[37]
    DIRECTION INPUT ;
    USE SIGNAL ;
    ANTENNAGATEAREA 0.247500 ;
    PORT
      LAYER met2 ;
        RECT 138.550 663.805 138.830 667.805 ;
    END
  END input_data[37]
  PIN input_data[38]
    DIRECTION INPUT ;
    USE SIGNAL ;
    ANTENNAGATEAREA 0.213000 ;
    PORT
      LAYER met2 ;
        RECT 140.850 663.805 141.130 667.805 ;
    END
  END input_data[38]
  PIN input_data[39]
    DIRECTION INPUT ;
    USE SIGNAL ;
    ANTENNAGATEAREA 0.213000 ;
    PORT
      LAYER met2 ;
        RECT 143.150 663.805 143.430 667.805 ;
    END
  END input_data[39]
  PIN input_data[3]
    DIRECTION INPUT ;
    USE SIGNAL ;
    ANTENNAGATEAREA 0.495000 ;
    PORT
      LAYER met2 ;
        RECT 60.350 663.805 60.630 667.805 ;
    END
  END input_data[3]
  PIN input_data[40]
    DIRECTION INPUT ;
    USE SIGNAL ;
    ANTENNAGATEAREA 0.213000 ;
    PORT
      LAYER met2 ;
        RECT 145.450 663.805 145.730 667.805 ;
    END
  END input_data[40]
  PIN input_data[41]
    DIRECTION INPUT ;
    USE SIGNAL ;
    ANTENNAGATEAREA 0.247500 ;
    PORT
      LAYER met2 ;
        RECT 147.750 663.805 148.030 667.805 ;
    END
  END input_data[41]
  PIN input_data[42]
    DIRECTION INPUT ;
    USE SIGNAL ;
    ANTENNAGATEAREA 0.196500 ;
    PORT
      LAYER met2 ;
        RECT 150.050 663.805 150.330 667.805 ;
    END
  END input_data[42]
  PIN input_data[43]
    DIRECTION INPUT ;
    USE SIGNAL ;
    ANTENNAGATEAREA 0.247500 ;
    PORT
      LAYER met2 ;
        RECT 152.350 663.805 152.630 667.805 ;
    END
  END input_data[43]
  PIN input_data[44]
    DIRECTION INPUT ;
    USE SIGNAL ;
    ANTENNAGATEAREA 0.213000 ;
    PORT
      LAYER met2 ;
        RECT 154.650 663.805 154.930 667.805 ;
    END
  END input_data[44]
  PIN input_data[45]
    DIRECTION INPUT ;
    USE SIGNAL ;
    ANTENNAGATEAREA 0.213000 ;
    PORT
      LAYER met2 ;
        RECT 156.950 663.805 157.230 667.805 ;
    END
  END input_data[45]
  PIN input_data[46]
    DIRECTION INPUT ;
    USE SIGNAL ;
    ANTENNAGATEAREA 0.247500 ;
    PORT
      LAYER met2 ;
        RECT 159.250 663.805 159.530 667.805 ;
    END
  END input_data[46]
  PIN input_data[47]
    DIRECTION INPUT ;
    USE SIGNAL ;
    ANTENNAGATEAREA 0.495000 ;
    PORT
      LAYER met2 ;
        RECT 161.550 663.805 161.830 667.805 ;
    END
  END input_data[47]
  PIN input_data[48]
    DIRECTION INPUT ;
    USE SIGNAL ;
    ANTENNAGATEAREA 0.213000 ;
    PORT
      LAYER met2 ;
        RECT 163.850 663.805 164.130 667.805 ;
    END
  END input_data[48]
  PIN input_data[49]
    DIRECTION INPUT ;
    USE SIGNAL ;
    ANTENNAGATEAREA 0.213000 ;
    PORT
      LAYER met2 ;
        RECT 166.150 663.805 166.430 667.805 ;
    END
  END input_data[49]
  PIN input_data[4]
    DIRECTION INPUT ;
    USE SIGNAL ;
    ANTENNAGATEAREA 0.196500 ;
    PORT
      LAYER met2 ;
        RECT 62.650 663.805 62.930 667.805 ;
    END
  END input_data[4]
  PIN input_data[50]
    DIRECTION INPUT ;
    USE SIGNAL ;
    ANTENNAGATEAREA 0.213000 ;
    PORT
      LAYER met2 ;
        RECT 168.450 663.805 168.730 667.805 ;
    END
  END input_data[50]
  PIN input_data[51]
    DIRECTION INPUT ;
    USE SIGNAL ;
    ANTENNAGATEAREA 0.159000 ;
    PORT
      LAYER met2 ;
        RECT 170.750 663.805 171.030 667.805 ;
    END
  END input_data[51]
  PIN input_data[52]
    DIRECTION INPUT ;
    USE SIGNAL ;
    ANTENNAGATEAREA 0.213000 ;
    PORT
      LAYER met2 ;
        RECT 173.050 663.805 173.330 667.805 ;
    END
  END input_data[52]
  PIN input_data[53]
    DIRECTION INPUT ;
    USE SIGNAL ;
    ANTENNAGATEAREA 0.213000 ;
    PORT
      LAYER met2 ;
        RECT 175.350 663.805 175.630 667.805 ;
    END
  END input_data[53]
  PIN input_data[54]
    DIRECTION INPUT ;
    USE SIGNAL ;
    ANTENNAGATEAREA 0.213000 ;
    PORT
      LAYER met2 ;
        RECT 177.650 663.805 177.930 667.805 ;
    END
  END input_data[54]
  PIN input_data[55]
    DIRECTION INPUT ;
    USE SIGNAL ;
    ANTENNAGATEAREA 0.213000 ;
    PORT
      LAYER met2 ;
        RECT 179.950 663.805 180.230 667.805 ;
    END
  END input_data[55]
  PIN input_data[56]
    DIRECTION INPUT ;
    USE SIGNAL ;
    ANTENNAGATEAREA 0.126000 ;
    PORT
      LAYER met2 ;
        RECT 182.250 663.805 182.530 667.805 ;
    END
  END input_data[56]
  PIN input_data[57]
    DIRECTION INPUT ;
    USE SIGNAL ;
    ANTENNAGATEAREA 0.213000 ;
    PORT
      LAYER met2 ;
        RECT 184.550 663.805 184.830 667.805 ;
    END
  END input_data[57]
  PIN input_data[58]
    DIRECTION INPUT ;
    USE SIGNAL ;
    ANTENNAGATEAREA 0.159000 ;
    PORT
      LAYER met2 ;
        RECT 186.850 663.805 187.130 667.805 ;
    END
  END input_data[58]
  PIN input_data[59]
    DIRECTION INPUT ;
    USE SIGNAL ;
    ANTENNAGATEAREA 0.196500 ;
    PORT
      LAYER met2 ;
        RECT 189.150 663.805 189.430 667.805 ;
    END
  END input_data[59]
  PIN input_data[5]
    DIRECTION INPUT ;
    USE SIGNAL ;
    ANTENNAGATEAREA 0.196500 ;
    PORT
      LAYER met2 ;
        RECT 64.950 663.805 65.230 667.805 ;
    END
  END input_data[5]
  PIN input_data[60]
    DIRECTION INPUT ;
    USE SIGNAL ;
    ANTENNAGATEAREA 0.196500 ;
    PORT
      LAYER met2 ;
        RECT 191.450 663.805 191.730 667.805 ;
    END
  END input_data[60]
  PIN input_data[61]
    DIRECTION INPUT ;
    USE SIGNAL ;
    ANTENNAGATEAREA 0.196500 ;
    PORT
      LAYER met2 ;
        RECT 193.750 663.805 194.030 667.805 ;
    END
  END input_data[61]
  PIN input_data[62]
    DIRECTION INPUT ;
    USE SIGNAL ;
    ANTENNAGATEAREA 0.196500 ;
    PORT
      LAYER met2 ;
        RECT 196.050 663.805 196.330 667.805 ;
    END
  END input_data[62]
  PIN input_data[63]
    DIRECTION INPUT ;
    USE SIGNAL ;
    ANTENNAGATEAREA 0.159000 ;
    PORT
      LAYER met2 ;
        RECT 198.350 663.805 198.630 667.805 ;
    END
  END input_data[63]
  PIN input_data[64]
    DIRECTION INPUT ;
    USE SIGNAL ;
    ANTENNAGATEAREA 0.247500 ;
    PORT
      LAYER met2 ;
        RECT 200.650 663.805 200.930 667.805 ;
    END
  END input_data[64]
  PIN input_data[65]
    DIRECTION INPUT ;
    USE SIGNAL ;
    ANTENNAGATEAREA 0.247500 ;
    PORT
      LAYER met2 ;
        RECT 202.950 663.805 203.230 667.805 ;
    END
  END input_data[65]
  PIN input_data[66]
    DIRECTION INPUT ;
    USE SIGNAL ;
    ANTENNAGATEAREA 0.196500 ;
    PORT
      LAYER met2 ;
        RECT 205.250 663.805 205.530 667.805 ;
    END
  END input_data[66]
  PIN input_data[67]
    DIRECTION INPUT ;
    USE SIGNAL ;
    ANTENNAGATEAREA 0.196500 ;
    PORT
      LAYER met2 ;
        RECT 207.550 663.805 207.830 667.805 ;
    END
  END input_data[67]
  PIN input_data[68]
    DIRECTION INPUT ;
    USE SIGNAL ;
    ANTENNAGATEAREA 0.196500 ;
    PORT
      LAYER met2 ;
        RECT 209.850 663.805 210.130 667.805 ;
    END
  END input_data[68]
  PIN input_data[69]
    DIRECTION INPUT ;
    USE SIGNAL ;
    ANTENNAGATEAREA 0.213000 ;
    PORT
      LAYER met2 ;
        RECT 212.150 663.805 212.430 667.805 ;
    END
  END input_data[69]
  PIN input_data[6]
    DIRECTION INPUT ;
    USE SIGNAL ;
    ANTENNAGATEAREA 0.196500 ;
    PORT
      LAYER met2 ;
        RECT 67.250 663.805 67.530 667.805 ;
    END
  END input_data[6]
  PIN input_data[70]
    DIRECTION INPUT ;
    USE SIGNAL ;
    ANTENNAGATEAREA 0.213000 ;
    PORT
      LAYER met2 ;
        RECT 214.450 663.805 214.730 667.805 ;
    END
  END input_data[70]
  PIN input_data[71]
    DIRECTION INPUT ;
    USE SIGNAL ;
    ANTENNAGATEAREA 0.213000 ;
    PORT
      LAYER met2 ;
        RECT 216.750 663.805 217.030 667.805 ;
    END
  END input_data[71]
  PIN input_data[72]
    DIRECTION INPUT ;
    USE SIGNAL ;
    ANTENNAGATEAREA 0.196500 ;
    PORT
      LAYER met2 ;
        RECT 219.050 663.805 219.330 667.805 ;
    END
  END input_data[72]
  PIN input_data[73]
    DIRECTION INPUT ;
    USE SIGNAL ;
    ANTENNAGATEAREA 0.196500 ;
    PORT
      LAYER met2 ;
        RECT 221.350 663.805 221.630 667.805 ;
    END
  END input_data[73]
  PIN input_data[74]
    DIRECTION INPUT ;
    USE SIGNAL ;
    ANTENNAGATEAREA 0.196500 ;
    PORT
      LAYER met2 ;
        RECT 223.650 663.805 223.930 667.805 ;
    END
  END input_data[74]
  PIN input_data[75]
    DIRECTION INPUT ;
    USE SIGNAL ;
    ANTENNAGATEAREA 0.196500 ;
    PORT
      LAYER met2 ;
        RECT 225.950 663.805 226.230 667.805 ;
    END
  END input_data[75]
  PIN input_data[76]
    DIRECTION INPUT ;
    USE SIGNAL ;
    ANTENNAGATEAREA 0.196500 ;
    PORT
      LAYER met2 ;
        RECT 228.250 663.805 228.530 667.805 ;
    END
  END input_data[76]
  PIN input_data[77]
    DIRECTION INPUT ;
    USE SIGNAL ;
    ANTENNAGATEAREA 0.196500 ;
    PORT
      LAYER met2 ;
        RECT 230.550 663.805 230.830 667.805 ;
    END
  END input_data[77]
  PIN input_data[78]
    DIRECTION INPUT ;
    USE SIGNAL ;
    ANTENNAGATEAREA 0.247500 ;
    PORT
      LAYER met2 ;
        RECT 232.850 663.805 233.130 667.805 ;
    END
  END input_data[78]
  PIN input_data[79]
    DIRECTION INPUT ;
    USE SIGNAL ;
    ANTENNAGATEAREA 0.213000 ;
    PORT
      LAYER met2 ;
        RECT 235.150 663.805 235.430 667.805 ;
    END
  END input_data[79]
  PIN input_data[7]
    DIRECTION INPUT ;
    USE SIGNAL ;
    ANTENNAGATEAREA 0.196500 ;
    PORT
      LAYER met2 ;
        RECT 69.550 663.805 69.830 667.805 ;
    END
  END input_data[7]
  PIN input_data[80]
    DIRECTION INPUT ;
    USE SIGNAL ;
    ANTENNAGATEAREA 0.495000 ;
    PORT
      LAYER met2 ;
        RECT 237.450 663.805 237.730 667.805 ;
    END
  END input_data[80]
  PIN input_data[81]
    DIRECTION INPUT ;
    USE SIGNAL ;
    ANTENNAGATEAREA 0.213000 ;
    PORT
      LAYER met2 ;
        RECT 239.750 663.805 240.030 667.805 ;
    END
  END input_data[81]
  PIN input_data[82]
    DIRECTION INPUT ;
    USE SIGNAL ;
    ANTENNAGATEAREA 0.196500 ;
    PORT
      LAYER met2 ;
        RECT 242.050 663.805 242.330 667.805 ;
    END
  END input_data[82]
  PIN input_data[83]
    DIRECTION INPUT ;
    USE SIGNAL ;
    ANTENNAGATEAREA 0.196500 ;
    PORT
      LAYER met2 ;
        RECT 244.350 663.805 244.630 667.805 ;
    END
  END input_data[83]
  PIN input_data[84]
    DIRECTION INPUT ;
    USE SIGNAL ;
    ANTENNAGATEAREA 0.159000 ;
    PORT
      LAYER met2 ;
        RECT 246.650 663.805 246.930 667.805 ;
    END
  END input_data[84]
  PIN input_data[85]
    DIRECTION INPUT ;
    USE SIGNAL ;
    ANTENNAGATEAREA 0.196500 ;
    PORT
      LAYER met2 ;
        RECT 248.950 663.805 249.230 667.805 ;
    END
  END input_data[85]
  PIN input_data[86]
    DIRECTION INPUT ;
    USE SIGNAL ;
    ANTENNAGATEAREA 0.196500 ;
    PORT
      LAYER met2 ;
        RECT 251.250 663.805 251.530 667.805 ;
    END
  END input_data[86]
  PIN input_data[87]
    DIRECTION INPUT ;
    USE SIGNAL ;
    ANTENNAGATEAREA 0.196500 ;
    PORT
      LAYER met2 ;
        RECT 253.550 663.805 253.830 667.805 ;
    END
  END input_data[87]
  PIN input_data[88]
    DIRECTION INPUT ;
    USE SIGNAL ;
    ANTENNAGATEAREA 0.196500 ;
    PORT
      LAYER met2 ;
        RECT 255.850 663.805 256.130 667.805 ;
    END
  END input_data[88]
  PIN input_data[89]
    DIRECTION INPUT ;
    USE SIGNAL ;
    ANTENNAGATEAREA 0.196500 ;
    PORT
      LAYER met2 ;
        RECT 258.150 663.805 258.430 667.805 ;
    END
  END input_data[89]
  PIN input_data[8]
    DIRECTION INPUT ;
    USE SIGNAL ;
    ANTENNAGATEAREA 0.196500 ;
    PORT
      LAYER met2 ;
        RECT 71.850 663.805 72.130 667.805 ;
    END
  END input_data[8]
  PIN input_data[90]
    DIRECTION INPUT ;
    USE SIGNAL ;
    ANTENNAGATEAREA 0.196500 ;
    PORT
      LAYER met2 ;
        RECT 260.450 663.805 260.730 667.805 ;
    END
  END input_data[90]
  PIN input_data[91]
    DIRECTION INPUT ;
    USE SIGNAL ;
    ANTENNAGATEAREA 0.159000 ;
    PORT
      LAYER met2 ;
        RECT 262.750 663.805 263.030 667.805 ;
    END
  END input_data[91]
  PIN input_data[92]
    DIRECTION INPUT ;
    USE SIGNAL ;
    ANTENNAGATEAREA 0.213000 ;
    PORT
      LAYER met2 ;
        RECT 265.050 663.805 265.330 667.805 ;
    END
  END input_data[92]
  PIN input_data[93]
    DIRECTION INPUT ;
    USE SIGNAL ;
    ANTENNAGATEAREA 0.196500 ;
    PORT
      LAYER met2 ;
        RECT 267.350 663.805 267.630 667.805 ;
    END
  END input_data[93]
  PIN input_data[94]
    DIRECTION INPUT ;
    USE SIGNAL ;
    ANTENNAGATEAREA 0.247500 ;
    PORT
      LAYER met2 ;
        RECT 269.650 663.805 269.930 667.805 ;
    END
  END input_data[94]
  PIN input_data[95]
    DIRECTION INPUT ;
    USE SIGNAL ;
    ANTENNAGATEAREA 0.126000 ;
    PORT
      LAYER met2 ;
        RECT 271.950 663.805 272.230 667.805 ;
    END
  END input_data[95]
  PIN input_data[96]
    DIRECTION INPUT ;
    USE SIGNAL ;
    ANTENNAGATEAREA 0.247500 ;
    PORT
      LAYER met2 ;
        RECT 274.250 663.805 274.530 667.805 ;
    END
  END input_data[96]
  PIN input_data[97]
    DIRECTION INPUT ;
    USE SIGNAL ;
    ANTENNAGATEAREA 0.213000 ;
    PORT
      LAYER met2 ;
        RECT 276.550 663.805 276.830 667.805 ;
    END
  END input_data[97]
  PIN input_data[98]
    DIRECTION INPUT ;
    USE SIGNAL ;
    ANTENNAGATEAREA 0.213000 ;
    PORT
      LAYER met2 ;
        RECT 278.850 663.805 279.130 667.805 ;
    END
  END input_data[98]
  PIN input_data[99]
    DIRECTION INPUT ;
    USE SIGNAL ;
    ANTENNAGATEAREA 0.247500 ;
    PORT
      LAYER met2 ;
        RECT 281.150 663.805 281.430 667.805 ;
    END
  END input_data[99]
  PIN input_data[9]
    DIRECTION INPUT ;
    USE SIGNAL ;
    ANTENNAGATEAREA 0.196500 ;
    PORT
      LAYER met2 ;
        RECT 74.150 663.805 74.430 667.805 ;
    END
  END input_data[9]
  PIN output_low[0]
    DIRECTION OUTPUT ;
    USE SIGNAL ;
    ANTENNADIFFAREA 0.445500 ;
    PORT
      LAYER met3 ;
        RECT 0.000 27.240 4.000 27.840 ;
    END
  END output_low[0]
  PIN output_low[10]
    DIRECTION OUTPUT ;
    USE SIGNAL ;
    ANTENNADIFFAREA 0.445500 ;
    PORT
      LAYER met3 ;
        RECT 0.000 435.240 4.000 435.840 ;
    END
  END output_low[10]
  PIN output_low[11]
    DIRECTION OUTPUT ;
    USE SIGNAL ;
    ANTENNADIFFAREA 0.445500 ;
    PORT
      LAYER met3 ;
        RECT 0.000 476.040 4.000 476.640 ;
    END
  END output_low[11]
  PIN output_low[12]
    DIRECTION OUTPUT ;
    USE SIGNAL ;
    ANTENNADIFFAREA 0.445500 ;
    PORT
      LAYER met3 ;
        RECT 0.000 516.840 4.000 517.440 ;
    END
  END output_low[12]
  PIN output_low[13]
    DIRECTION OUTPUT ;
    USE SIGNAL ;
    ANTENNADIFFAREA 0.445500 ;
    PORT
      LAYER met3 ;
        RECT 0.000 557.640 4.000 558.240 ;
    END
  END output_low[13]
  PIN output_low[14]
    DIRECTION OUTPUT ;
    USE SIGNAL ;
    ANTENNADIFFAREA 0.445500 ;
    PORT
      LAYER met3 ;
        RECT 0.000 598.440 4.000 599.040 ;
    END
  END output_low[14]
  PIN output_low[15]
    DIRECTION OUTPUT ;
    USE SIGNAL ;
    ANTENNADIFFAREA 0.445500 ;
    PORT
      LAYER met3 ;
        RECT 0.000 639.240 4.000 639.840 ;
    END
  END output_low[15]
  PIN output_low[1]
    DIRECTION OUTPUT ;
    USE SIGNAL ;
    ANTENNADIFFAREA 0.445500 ;
    PORT
      LAYER met3 ;
        RECT 0.000 68.040 4.000 68.640 ;
    END
  END output_low[1]
  PIN output_low[2]
    DIRECTION OUTPUT ;
    USE SIGNAL ;
    ANTENNADIFFAREA 0.445500 ;
    PORT
      LAYER met3 ;
        RECT 0.000 108.840 4.000 109.440 ;
    END
  END output_low[2]
  PIN output_low[3]
    DIRECTION OUTPUT ;
    USE SIGNAL ;
    ANTENNADIFFAREA 0.445500 ;
    PORT
      LAYER met3 ;
        RECT 0.000 149.640 4.000 150.240 ;
    END
  END output_low[3]
  PIN output_low[4]
    DIRECTION OUTPUT ;
    USE SIGNAL ;
    ANTENNADIFFAREA 0.445500 ;
    PORT
      LAYER met3 ;
        RECT 0.000 190.440 4.000 191.040 ;
    END
  END output_low[4]
  PIN output_low[5]
    DIRECTION OUTPUT ;
    USE SIGNAL ;
    ANTENNADIFFAREA 0.445500 ;
    PORT
      LAYER met3 ;
        RECT 0.000 231.240 4.000 231.840 ;
    END
  END output_low[5]
  PIN output_low[6]
    DIRECTION OUTPUT ;
    USE SIGNAL ;
    ANTENNADIFFAREA 0.445500 ;
    PORT
      LAYER met3 ;
        RECT 0.000 272.040 4.000 272.640 ;
    END
  END output_low[6]
  PIN output_low[7]
    DIRECTION OUTPUT ;
    USE SIGNAL ;
    ANTENNADIFFAREA 0.445500 ;
    PORT
      LAYER met3 ;
        RECT 0.000 312.840 4.000 313.440 ;
    END
  END output_low[7]
  PIN output_low[8]
    DIRECTION OUTPUT ;
    USE SIGNAL ;
    ANTENNADIFFAREA 0.445500 ;
    PORT
      LAYER met3 ;
        RECT 0.000 353.640 4.000 354.240 ;
    END
  END output_low[8]
  PIN output_low[9]
    DIRECTION OUTPUT ;
    USE SIGNAL ;
    ANTENNADIFFAREA 0.445500 ;
    PORT
      LAYER met3 ;
        RECT 0.000 394.440 4.000 395.040 ;
    END
  END output_low[9]
  PIN tap[0]
    DIRECTION INPUT ;
    USE SIGNAL ;
    ANTENNAGATEAREA 0.213000 ;
    PORT
      LAYER met2 ;
        RECT 81.970 0.000 82.250 4.000 ;
    END
  END tap[0]
  PIN tap[1]
    DIRECTION INPUT ;
    USE SIGNAL ;
    ANTENNAGATEAREA 0.213000 ;
    PORT
      LAYER met2 ;
        RECT 246.190 0.000 246.470 4.000 ;
    END
  END tap[1]
  PIN tap[2]
    DIRECTION INPUT ;
    USE SIGNAL ;
    ANTENNAGATEAREA 0.213000 ;
    PORT
      LAYER met2 ;
        RECT 410.410 0.000 410.690 4.000 ;
    END
  END tap[2]
  PIN tap[3]
    DIRECTION INPUT ;
    USE SIGNAL ;
    ANTENNAGATEAREA 0.213000 ;
    PORT
      LAYER met2 ;
        RECT 574.630 0.000 574.910 4.000 ;
    END
  END tap[3]
  OBS
      LAYER li1 ;
        RECT 5.520 10.795 651.360 655.605 ;
      LAYER met1 ;
        RECT 2.830 10.640 651.660 659.220 ;
      LAYER met2 ;
        RECT 2.390 663.525 53.170 664.090 ;
        RECT 54.010 663.525 55.470 664.090 ;
        RECT 56.310 663.525 57.770 664.090 ;
        RECT 58.610 663.525 60.070 664.090 ;
        RECT 60.910 663.525 62.370 664.090 ;
        RECT 63.210 663.525 64.670 664.090 ;
        RECT 65.510 663.525 66.970 664.090 ;
        RECT 67.810 663.525 69.270 664.090 ;
        RECT 70.110 663.525 71.570 664.090 ;
        RECT 72.410 663.525 73.870 664.090 ;
        RECT 74.710 663.525 76.170 664.090 ;
        RECT 77.010 663.525 78.470 664.090 ;
        RECT 79.310 663.525 80.770 664.090 ;
        RECT 81.610 663.525 83.070 664.090 ;
        RECT 83.910 663.525 85.370 664.090 ;
        RECT 86.210 663.525 87.670 664.090 ;
        RECT 88.510 663.525 89.970 664.090 ;
        RECT 90.810 663.525 92.270 664.090 ;
        RECT 93.110 663.525 94.570 664.090 ;
        RECT 95.410 663.525 96.870 664.090 ;
        RECT 97.710 663.525 99.170 664.090 ;
        RECT 100.010 663.525 101.470 664.090 ;
        RECT 102.310 663.525 103.770 664.090 ;
        RECT 104.610 663.525 106.070 664.090 ;
        RECT 106.910 663.525 108.370 664.090 ;
        RECT 109.210 663.525 110.670 664.090 ;
        RECT 111.510 663.525 112.970 664.090 ;
        RECT 113.810 663.525 115.270 664.090 ;
        RECT 116.110 663.525 117.570 664.090 ;
        RECT 118.410 663.525 119.870 664.090 ;
        RECT 120.710 663.525 122.170 664.090 ;
        RECT 123.010 663.525 124.470 664.090 ;
        RECT 125.310 663.525 126.770 664.090 ;
        RECT 127.610 663.525 129.070 664.090 ;
        RECT 129.910 663.525 131.370 664.090 ;
        RECT 132.210 663.525 133.670 664.090 ;
        RECT 134.510 663.525 135.970 664.090 ;
        RECT 136.810 663.525 138.270 664.090 ;
        RECT 139.110 663.525 140.570 664.090 ;
        RECT 141.410 663.525 142.870 664.090 ;
        RECT 143.710 663.525 145.170 664.090 ;
        RECT 146.010 663.525 147.470 664.090 ;
        RECT 148.310 663.525 149.770 664.090 ;
        RECT 150.610 663.525 152.070 664.090 ;
        RECT 152.910 663.525 154.370 664.090 ;
        RECT 155.210 663.525 156.670 664.090 ;
        RECT 157.510 663.525 158.970 664.090 ;
        RECT 159.810 663.525 161.270 664.090 ;
        RECT 162.110 663.525 163.570 664.090 ;
        RECT 164.410 663.525 165.870 664.090 ;
        RECT 166.710 663.525 168.170 664.090 ;
        RECT 169.010 663.525 170.470 664.090 ;
        RECT 171.310 663.525 172.770 664.090 ;
        RECT 173.610 663.525 175.070 664.090 ;
        RECT 175.910 663.525 177.370 664.090 ;
        RECT 178.210 663.525 179.670 664.090 ;
        RECT 180.510 663.525 181.970 664.090 ;
        RECT 182.810 663.525 184.270 664.090 ;
        RECT 185.110 663.525 186.570 664.090 ;
        RECT 187.410 663.525 188.870 664.090 ;
        RECT 189.710 663.525 191.170 664.090 ;
        RECT 192.010 663.525 193.470 664.090 ;
        RECT 194.310 663.525 195.770 664.090 ;
        RECT 196.610 663.525 198.070 664.090 ;
        RECT 198.910 663.525 200.370 664.090 ;
        RECT 201.210 663.525 202.670 664.090 ;
        RECT 203.510 663.525 204.970 664.090 ;
        RECT 205.810 663.525 207.270 664.090 ;
        RECT 208.110 663.525 209.570 664.090 ;
        RECT 210.410 663.525 211.870 664.090 ;
        RECT 212.710 663.525 214.170 664.090 ;
        RECT 215.010 663.525 216.470 664.090 ;
        RECT 217.310 663.525 218.770 664.090 ;
        RECT 219.610 663.525 221.070 664.090 ;
        RECT 221.910 663.525 223.370 664.090 ;
        RECT 224.210 663.525 225.670 664.090 ;
        RECT 226.510 663.525 227.970 664.090 ;
        RECT 228.810 663.525 230.270 664.090 ;
        RECT 231.110 663.525 232.570 664.090 ;
        RECT 233.410 663.525 234.870 664.090 ;
        RECT 235.710 663.525 237.170 664.090 ;
        RECT 238.010 663.525 239.470 664.090 ;
        RECT 240.310 663.525 241.770 664.090 ;
        RECT 242.610 663.525 244.070 664.090 ;
        RECT 244.910 663.525 246.370 664.090 ;
        RECT 247.210 663.525 248.670 664.090 ;
        RECT 249.510 663.525 250.970 664.090 ;
        RECT 251.810 663.525 253.270 664.090 ;
        RECT 254.110 663.525 255.570 664.090 ;
        RECT 256.410 663.525 257.870 664.090 ;
        RECT 258.710 663.525 260.170 664.090 ;
        RECT 261.010 663.525 262.470 664.090 ;
        RECT 263.310 663.525 264.770 664.090 ;
        RECT 265.610 663.525 267.070 664.090 ;
        RECT 267.910 663.525 269.370 664.090 ;
        RECT 270.210 663.525 271.670 664.090 ;
        RECT 272.510 663.525 273.970 664.090 ;
        RECT 274.810 663.525 276.270 664.090 ;
        RECT 277.110 663.525 278.570 664.090 ;
        RECT 279.410 663.525 280.870 664.090 ;
        RECT 281.710 663.525 283.170 664.090 ;
        RECT 284.010 663.525 285.470 664.090 ;
        RECT 286.310 663.525 287.770 664.090 ;
        RECT 288.610 663.525 290.070 664.090 ;
        RECT 290.910 663.525 292.370 664.090 ;
        RECT 293.210 663.525 294.670 664.090 ;
        RECT 295.510 663.525 296.970 664.090 ;
        RECT 297.810 663.525 299.270 664.090 ;
        RECT 300.110 663.525 301.570 664.090 ;
        RECT 302.410 663.525 303.870 664.090 ;
        RECT 304.710 663.525 306.170 664.090 ;
        RECT 307.010 663.525 308.470 664.090 ;
        RECT 309.310 663.525 310.770 664.090 ;
        RECT 311.610 663.525 313.070 664.090 ;
        RECT 313.910 663.525 315.370 664.090 ;
        RECT 316.210 663.525 317.670 664.090 ;
        RECT 318.510 663.525 319.970 664.090 ;
        RECT 320.810 663.525 322.270 664.090 ;
        RECT 323.110 663.525 324.570 664.090 ;
        RECT 325.410 663.525 326.870 664.090 ;
        RECT 327.710 663.525 329.170 664.090 ;
        RECT 330.010 663.525 331.470 664.090 ;
        RECT 332.310 663.525 333.770 664.090 ;
        RECT 334.610 663.525 336.070 664.090 ;
        RECT 336.910 663.525 338.370 664.090 ;
        RECT 339.210 663.525 340.670 664.090 ;
        RECT 341.510 663.525 342.970 664.090 ;
        RECT 343.810 663.525 345.270 664.090 ;
        RECT 346.110 663.525 347.570 664.090 ;
        RECT 348.410 663.525 349.870 664.090 ;
        RECT 350.710 663.525 352.170 664.090 ;
        RECT 353.010 663.525 354.470 664.090 ;
        RECT 355.310 663.525 356.770 664.090 ;
        RECT 357.610 663.525 359.070 664.090 ;
        RECT 359.910 663.525 361.370 664.090 ;
        RECT 362.210 663.525 363.670 664.090 ;
        RECT 364.510 663.525 365.970 664.090 ;
        RECT 366.810 663.525 368.270 664.090 ;
        RECT 369.110 663.525 370.570 664.090 ;
        RECT 371.410 663.525 372.870 664.090 ;
        RECT 373.710 663.525 375.170 664.090 ;
        RECT 376.010 663.525 377.470 664.090 ;
        RECT 378.310 663.525 379.770 664.090 ;
        RECT 380.610 663.525 382.070 664.090 ;
        RECT 382.910 663.525 384.370 664.090 ;
        RECT 385.210 663.525 386.670 664.090 ;
        RECT 387.510 663.525 388.970 664.090 ;
        RECT 389.810 663.525 391.270 664.090 ;
        RECT 392.110 663.525 393.570 664.090 ;
        RECT 394.410 663.525 395.870 664.090 ;
        RECT 396.710 663.525 398.170 664.090 ;
        RECT 399.010 663.525 400.470 664.090 ;
        RECT 401.310 663.525 402.770 664.090 ;
        RECT 403.610 663.525 405.070 664.090 ;
        RECT 405.910 663.525 407.370 664.090 ;
        RECT 408.210 663.525 409.670 664.090 ;
        RECT 410.510 663.525 411.970 664.090 ;
        RECT 412.810 663.525 414.270 664.090 ;
        RECT 415.110 663.525 416.570 664.090 ;
        RECT 417.410 663.525 418.870 664.090 ;
        RECT 419.710 663.525 421.170 664.090 ;
        RECT 422.010 663.525 423.470 664.090 ;
        RECT 424.310 663.525 425.770 664.090 ;
        RECT 426.610 663.525 428.070 664.090 ;
        RECT 428.910 663.525 430.370 664.090 ;
        RECT 431.210 663.525 432.670 664.090 ;
        RECT 433.510 663.525 434.970 664.090 ;
        RECT 435.810 663.525 437.270 664.090 ;
        RECT 438.110 663.525 439.570 664.090 ;
        RECT 440.410 663.525 441.870 664.090 ;
        RECT 442.710 663.525 444.170 664.090 ;
        RECT 445.010 663.525 446.470 664.090 ;
        RECT 447.310 663.525 448.770 664.090 ;
        RECT 449.610 663.525 451.070 664.090 ;
        RECT 451.910 663.525 453.370 664.090 ;
        RECT 454.210 663.525 455.670 664.090 ;
        RECT 456.510 663.525 457.970 664.090 ;
        RECT 458.810 663.525 460.270 664.090 ;
        RECT 461.110 663.525 462.570 664.090 ;
        RECT 463.410 663.525 464.870 664.090 ;
        RECT 465.710 663.525 467.170 664.090 ;
        RECT 468.010 663.525 469.470 664.090 ;
        RECT 470.310 663.525 471.770 664.090 ;
        RECT 472.610 663.525 474.070 664.090 ;
        RECT 474.910 663.525 476.370 664.090 ;
        RECT 477.210 663.525 478.670 664.090 ;
        RECT 479.510 663.525 480.970 664.090 ;
        RECT 481.810 663.525 483.270 664.090 ;
        RECT 484.110 663.525 485.570 664.090 ;
        RECT 486.410 663.525 487.870 664.090 ;
        RECT 488.710 663.525 490.170 664.090 ;
        RECT 491.010 663.525 492.470 664.090 ;
        RECT 493.310 663.525 494.770 664.090 ;
        RECT 495.610 663.525 497.070 664.090 ;
        RECT 497.910 663.525 499.370 664.090 ;
        RECT 500.210 663.525 501.670 664.090 ;
        RECT 502.510 663.525 503.970 664.090 ;
        RECT 504.810 663.525 506.270 664.090 ;
        RECT 507.110 663.525 508.570 664.090 ;
        RECT 509.410 663.525 510.870 664.090 ;
        RECT 511.710 663.525 513.170 664.090 ;
        RECT 514.010 663.525 515.470 664.090 ;
        RECT 516.310 663.525 517.770 664.090 ;
        RECT 518.610 663.525 520.070 664.090 ;
        RECT 520.910 663.525 522.370 664.090 ;
        RECT 523.210 663.525 524.670 664.090 ;
        RECT 525.510 663.525 526.970 664.090 ;
        RECT 527.810 663.525 529.270 664.090 ;
        RECT 530.110 663.525 531.570 664.090 ;
        RECT 532.410 663.525 533.870 664.090 ;
        RECT 534.710 663.525 536.170 664.090 ;
        RECT 537.010 663.525 538.470 664.090 ;
        RECT 539.310 663.525 540.770 664.090 ;
        RECT 541.610 663.525 543.070 664.090 ;
        RECT 543.910 663.525 545.370 664.090 ;
        RECT 546.210 663.525 547.670 664.090 ;
        RECT 548.510 663.525 549.970 664.090 ;
        RECT 550.810 663.525 552.270 664.090 ;
        RECT 553.110 663.525 554.570 664.090 ;
        RECT 555.410 663.525 556.870 664.090 ;
        RECT 557.710 663.525 559.170 664.090 ;
        RECT 560.010 663.525 561.470 664.090 ;
        RECT 562.310 663.525 563.770 664.090 ;
        RECT 564.610 663.525 566.070 664.090 ;
        RECT 566.910 663.525 568.370 664.090 ;
        RECT 569.210 663.525 570.670 664.090 ;
        RECT 571.510 663.525 572.970 664.090 ;
        RECT 573.810 663.525 575.270 664.090 ;
        RECT 576.110 663.525 577.570 664.090 ;
        RECT 578.410 663.525 579.870 664.090 ;
        RECT 580.710 663.525 582.170 664.090 ;
        RECT 583.010 663.525 584.470 664.090 ;
        RECT 585.310 663.525 586.770 664.090 ;
        RECT 587.610 663.525 589.070 664.090 ;
        RECT 589.910 663.525 591.370 664.090 ;
        RECT 592.210 663.525 593.670 664.090 ;
        RECT 594.510 663.525 595.970 664.090 ;
        RECT 596.810 663.525 598.270 664.090 ;
        RECT 599.110 663.525 600.570 664.090 ;
        RECT 601.410 663.525 602.870 664.090 ;
        RECT 603.710 663.525 648.960 664.090 ;
        RECT 2.390 4.280 648.960 663.525 ;
        RECT 2.390 4.000 81.690 4.280 ;
        RECT 82.530 4.000 245.910 4.280 ;
        RECT 246.750 4.000 410.130 4.280 ;
        RECT 410.970 4.000 574.350 4.280 ;
        RECT 575.190 4.000 648.960 4.280 ;
      LAYER met3 ;
        RECT 2.365 640.240 653.085 655.685 ;
        RECT 4.400 638.840 653.085 640.240 ;
        RECT 2.365 599.440 653.085 638.840 ;
        RECT 4.400 598.040 653.085 599.440 ;
        RECT 2.365 558.640 653.085 598.040 ;
        RECT 4.400 557.240 653.085 558.640 ;
        RECT 2.365 517.840 653.085 557.240 ;
        RECT 4.400 516.440 653.085 517.840 ;
        RECT 2.365 477.040 653.085 516.440 ;
        RECT 4.400 475.640 653.085 477.040 ;
        RECT 2.365 436.240 653.085 475.640 ;
        RECT 4.400 434.840 653.085 436.240 ;
        RECT 2.365 395.440 653.085 434.840 ;
        RECT 4.400 394.040 653.085 395.440 ;
        RECT 2.365 354.640 653.085 394.040 ;
        RECT 4.400 353.240 653.085 354.640 ;
        RECT 2.365 334.240 653.085 353.240 ;
        RECT 2.365 332.840 652.685 334.240 ;
        RECT 2.365 313.840 653.085 332.840 ;
        RECT 4.400 312.440 653.085 313.840 ;
        RECT 2.365 273.040 653.085 312.440 ;
        RECT 4.400 271.640 653.085 273.040 ;
        RECT 2.365 232.240 653.085 271.640 ;
        RECT 4.400 230.840 653.085 232.240 ;
        RECT 2.365 191.440 653.085 230.840 ;
        RECT 4.400 190.040 653.085 191.440 ;
        RECT 2.365 150.640 653.085 190.040 ;
        RECT 4.400 149.240 653.085 150.640 ;
        RECT 2.365 109.840 653.085 149.240 ;
        RECT 4.400 108.440 653.085 109.840 ;
        RECT 2.365 69.040 653.085 108.440 ;
        RECT 4.400 67.640 653.085 69.040 ;
        RECT 2.365 28.240 653.085 67.640 ;
        RECT 4.400 26.840 653.085 28.240 ;
        RECT 2.365 10.715 653.085 26.840 ;
      LAYER met4 ;
        RECT 5.815 47.775 20.640 652.625 ;
        RECT 23.040 47.775 23.940 652.625 ;
        RECT 26.340 47.775 174.240 652.625 ;
        RECT 176.640 47.775 177.540 652.625 ;
        RECT 179.940 47.775 327.840 652.625 ;
        RECT 330.240 47.775 331.140 652.625 ;
        RECT 333.540 47.775 481.440 652.625 ;
        RECT 483.840 47.775 484.740 652.625 ;
        RECT 487.140 47.775 635.040 652.625 ;
        RECT 637.440 47.775 638.340 652.625 ;
        RECT 640.740 47.775 642.785 652.625 ;
  END
END lowpass
END LIBRARY

